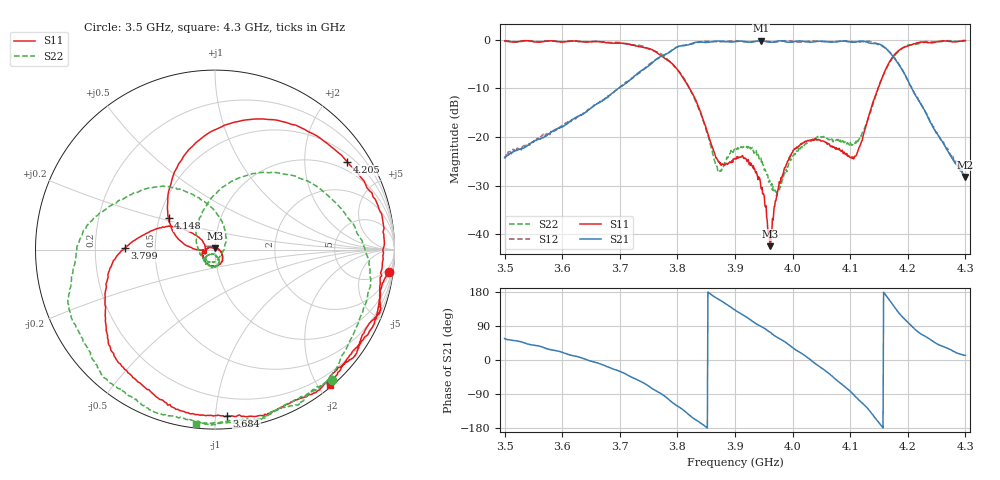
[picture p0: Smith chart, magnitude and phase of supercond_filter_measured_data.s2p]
# HZ S RI R 50.00000
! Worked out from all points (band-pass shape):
!   801 points, 3.5 GHz to 4.3 GHz, reference 50 ohm
!   highest |S21| = -0.18 dB at 3.945 GHz (marker M1); lowest = -28.2 dB at 4.3 GHz (marker M2)
!   |S21| within 3 dB of the highest: 3.775 GHz to 4.173 GHz (397.7 MHz wide, 10 % of centre)
!   lowest |S11| = -42.5 dB at 3.961 GHz (marker M3), VSWR 1.02, Z = 50.1 + j0.746 ohm
!   |S11| at or under -10 dB: 3.821 GHz to 4.148 GHz (327.2 MHz wide, 8.21 % of centre)
!   |S22| runs from -32.1 to -0.1 dB; largest |S21 - S12| = 0.051
!   S11 on the Smith chart (normalised r, x): 3.5 GHz: 3, -15; 3.684 GHz: 0.08, -1.07; 3.799 GHz: 0.33, +0.01; 4.148 GHz: 0.56, +0.22; 4.205 GHz: 0.71, +3.17; 4.3 GHz: 0.04, -2.16
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3.5e9  0.967 -0.124  0.0336 0.0513  0.0369 0.0512  0.654 -0.726
3.634e9  0.483 -0.827  0.169 0.0163  0.169 0.0104  -0.134 -0.95
3.684e9  0.0656 -0.926  0.255 -0.099  0.252 -0.1  -0.523 -0.782
3.734e9  -0.43 -0.737  0.27 -0.384  0.252 -0.379  -0.81 -0.341
3.767e9  -0.61 -0.382  0.0593 -0.651  0.0557 -0.642  -0.738 0.0909
3.799e9  -0.504 0.00732  -0.426 -0.728  -0.43 -0.723  -0.365 0.345
3.838e9  -0.163 0.109  -0.913 -0.264  -0.927 -0.238  0.0193 0.187
3.87e9  -0.0554 0.017  -0.924 0.308  -0.903 0.307  0.0447 -0.00567
3.9e9  -0.0568 -0.0203  -0.638 0.714  -0.646 0.73  -0.0177 -0.0709
3.945e9  -0.0278 0.0109  0.0242 0.979  0.0374 0.98  -0.0477 -0.0372
3.961e9  0.000904 0.00745  0.278 0.905  0.278 0.919  -0.0222 -0.0253
3.99e9  0.0403 -0.0349  0.679 0.663  0.719 0.666  0.013 -0.0418
4.034e9  -0.00778 -0.0939  0.947 -0.0597  0.968 -0.0646  0.0059 -0.0922
4.061e9  -0.0549 -0.0662  0.802 -0.523  0.795 -0.539  -0.0243 -0.0924
4.098e9  -0.0622 -0.00891  0.173 -0.941  0.162 -0.949  -0.0653 -0.0519
4.124e9  -0.111 0.00187  -0.455 -0.853  -0.484 -0.836  -0.103 0.0598
4.148e9  -0.259 0.174  -0.868 -0.281  -0.852 -0.286  0.00485 0.31
4.167e9  -0.144 0.559  -0.719 0.257  -0.707 0.276  0.372 0.423
4.185e9  0.294 0.725  -0.3 0.458  -0.309 0.462  0.755 0.161
4.205e9  0.736 0.489  -0.0126 0.333  -0.00615 0.335  0.849 -0.266
4.237e9  0.937 -0.0538  0.0834 0.125  0.087 0.127  0.581 -0.768
4.3e9  0.639 -0.752  0.0379 0.00835  0.0363 0.00776  -0.107 -0.973
